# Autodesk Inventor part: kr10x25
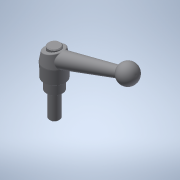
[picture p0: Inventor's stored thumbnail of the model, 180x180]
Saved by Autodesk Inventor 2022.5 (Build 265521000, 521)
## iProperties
Created: 2016-12
Part Number: kr10x25
Material: 一般
Document SubType Name: Modeling
Designer: imaocorp
Density: 1 g/cm^3
Appearance: 既定
Author: imaocorp
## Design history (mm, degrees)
node "kr10x25.x_t1"
node "kr10x25"
node "Base1"
